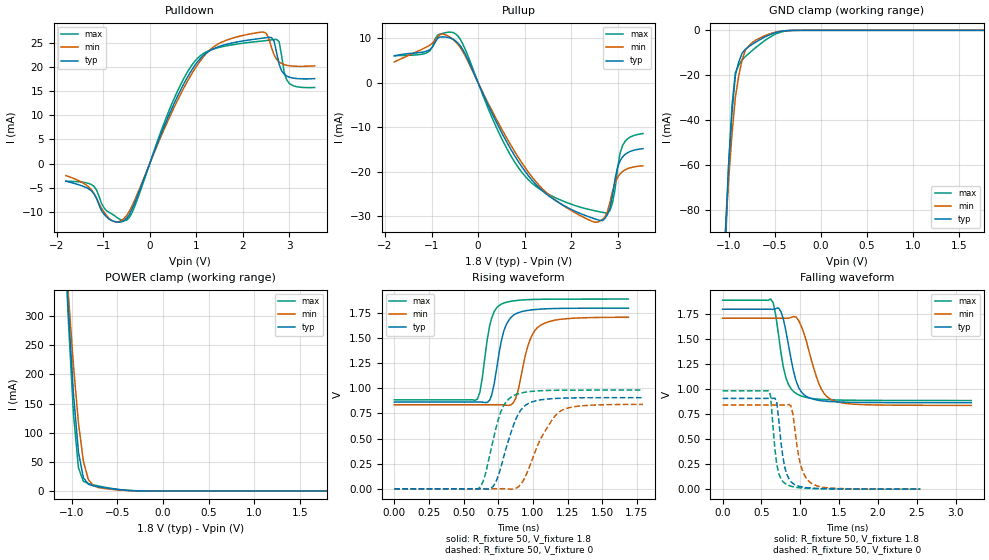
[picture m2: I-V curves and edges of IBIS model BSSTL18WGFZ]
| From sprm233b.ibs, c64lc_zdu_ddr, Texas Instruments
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|   Model Cell BSSTL18WGFZ
[Model]   BSSTL18WGFZ
Model_type   I/O
Polarity   Non-Inverting
Enable   Active-Low
Vinl =  0.8
Vinh =  1
Cref =  15.0000pF
Rref =  100.0000M
Vref =  0V
Vmeas =  0.9
C_comp   1.243651p   1.166975p   1.3173p
[Model Spec]
Vinl   0.8   0.755   0.845
Vinh   1   0.955   1.045
[Temperature Range]   25   125   -40
[Voltage Range]   1.8   1.71   1.89
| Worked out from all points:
|   slope of the pulldown table from 0 to 0.27 V, typ, clamps not added: 40.2 ohm
|   slope of the pullup table from 0 to 0.27 V, typ, clamps not added: 43.4 ohm
|   GND clamp passes 1 mA (typ) near -0.49 V on its own axis
|   POWER clamp passes 1 mA (typ) near -0.39 V on its own axis
|   rising waveform, R_fixture 50, V_fixture 1.8: 20-80 % time 80.1ps typ, 97.2ps min, 67.3ps max; typ from 0.864 V to 1.8 V
|   rising waveform, R_fixture 50, V_fixture 0: 20-80 % time 126ps typ, 172ps min, 109ps max; typ from 0 V to 0.908 V
|   falling waveform, R_fixture 50, V_fixture 1.8: 20-80 % time 155ps typ, 208ps min, 135ps max; typ from 1.8 V to 0.865 V
|   falling waveform, R_fixture 50, V_fixture 0: 20-80 % time 96.2ps typ, 117ps min, 79.5ps max; typ from 0.908 V to 0.001 V
[POWER_clamp]
|   voltage   I(typ)   I(min)   I(max)
-1.8V     2.924A     2.487A     3.338A
-1.055V   360.4mA    379.2mA    352.9mA
-1.036V   307mA      335.2mA    290.5mA
-1.018V   260.5mA    295.4mA    238.1mA
-981.8mV  167.5mA    215.8mA    133.1mA
-927.3mV  67.32mA    117.4mA    40.14mA
-872.7mV  22.56mA    51.06mA    16.61mA
-818.2mV  11.6mA     19.66mA    12.51mA
-763.6mV  8.74mA     9.202mA    10.43mA
-654.5mV  5.816mA    4.325mA    6.849mA
-272.7mV  209.5uA    104.6uA    156.2uA
1.8V      20.65nA    121nA      17.98nA
[Pulldown]
|   voltage   I(typ)   I(min)   I(max)
-1.8V     -3.616mA   -2.48mA    -3.623mA
-1.2V     -6.175mA   -6.104mA   -4.679mA
-818.2mV  -11.73mA   -11.74mA   -10.36mA
-490.9mV  -11.25mA   -10.65mA   -11.63mA
654.5mV   15.01mA    14.16mA    16.12mA
1.309V    23.41mA    23.6mA     23.46mA
2.455V    25.94mA    27.14mA    25.35mA
2.618V    26.01mA    23.98mA    25.55mA
2.727V    22.94mA    21.54mA    25.65mA
2.836V    19.15mA    20.65mA    22.22mA
3V        17.85mA    20.21mA    16.58mA
3.545V    17.54mA    20.19mA    15.71mA
[Pullup]
|   voltage   I(typ)   I(min)   I(max)
-1.8V     5.97mA     4.648mA    6.042mA
-1.091V   7.105mA    8.064mA    6.729mA
-818.2mV  10.22mA    10.77mA    10.87mA
-490.9mV  9.425mA    9.254mA    11mA
872.7mV   -17.83mA   -16.9mA    -19.16mA
1.418V    -24.61mA   -24.22mA   -24.52mA
2.182V    -29.34mA   -29.77mA   -27.93mA
2.564V    -30.79mA   -31.35mA   -28.9mA
2.836V    -28.2mA    -26.82mA   -28.68mA
3V        -19.04mA   -21.3mA    -19.15mA
3.109V    -16.66mA   -19.95mA   -14.1mA
3.545V    -14.83mA   -18.7mA    -11.44mA
[GND_clamp]
|   voltage   I(typ)   I(min)   I(max)
-1.8V     -3.609A    -2.849A    -4.282A
-1.036V   -90.86mA   -90.81mA   -98.4mA
-1V       -59.97mA   -66.44mA   -59.97mA
-963.6mV  -36.36mA   -46.14mA   -33.47mA
-927.3mV  -20.02mA   -29.92mA   -18.88mA
-890.9mV  -14.12mA   -20.26mA   -15.57mA
-854.5mV  -10.24mA   -13.24mA   -13.16mA
-818.2mV  -8.387mA   -8.861mA   -11.65mA
-709.1mV  -5.316mA   -4.454mA   -7.779mA
-490.9mV  -974.7uA   -808.7uA   -1.627mA
-345.5mV  -83.88uA   -97.13uA   -147.7uA
1.764V    -13.07nA   612.8nA    1.397nA
[Ramp]
| variable   typ   min   max
dV/dt_f  0.7607424/0.2533543n  0.7131334/0.3339664n  0.8127808/0.2287211n
dV/dt_r  0.7293766/0.1945862n   0.677097/0.252619n   0.7897642/0.1720576n
R_load = 50
[Rising Waveform]
R_fixture = 50
V_fixture = 1.8
V_fixture_min = 1.71
V_fixture_max = 1.89
|   time   V(typ)   V(min)   V(max)
0s        863.6mV    836.9mV    886mV
600ps     863.6mV    836.9mV    894.1mV
618ps     864.2mV    836.9mV    966.2mV
669ps     859.8mV    836.9mV    1.473V
702ps     929.5mV    836.8mV    1.698V
789ps     1.567V     835.2mV    1.849V
876ps     1.743V     900.4mV    1.875V
963ps     1.777V     1.421V     1.884V
1.047ns   1.789V     1.621V     1.887V
1.689ns   1.799V     1.708V     1.89V
[Rising Waveform]
R_fixture = 50
V_fixture = 0
V_fixture_min = 0
V_fixture_max = 0
|   time   V(typ)   V(min)   V(max)
0s        46.69uV    44.04uV    44.81uV
603ps     70.93uV    43.61uV    -1.627mV
657ps     -1.173mV   60.84uV    143.9mV
732ps     66.53mV    43.83uV    597.2mV
786ps     301.8mV    903.3uV    821mV
879ps     700.5mV    5.422mV    938.9mV
969ps     851mV      197.5mV    967.1mV
1.062ns   887mV      513.7mV    977.2mV
1.191ns   901.4mV    766.2mV    981.8mV
1.794ns   907.7mV    840.5mV    983.6mV
[Falling Waveform]
R_fixture = 50
V_fixture = 1.8
V_fixture_min = 1.71
V_fixture_max = 1.89
|   time   V(typ)   V(min)   V(max)
0s        1.8V       1.71V      1.89V
618ps     1.8V       1.71V      1.902V
651ps     1.799V     1.71V      1.864V
717ps     1.814V     1.71V      1.559V
813ps     1.588V     1.709V     1.118V
912ps     1.181V     1.727V     977.9mV
1.011ns   974.9mV    1.634V     932.9mV
1.239ns   888.5mV    1.056V     900.5mV
1.401ns   876.1mV    895.2mV    894mV
3.201ns   864.8mV    838.6mV    886.8mV
[Falling Waveform]
R_fixture = 50
V_fixture = 0
V_fixture_min = 0
V_fixture_max = 0
|   time   V(typ)   V(min)   V(max)
0s        908.3mV    842.3mV    983.8mV
594ps     908.3mV    842.3mV    986.6mV
618ps     908.3mV    842.3mV    930mV
696ps     875.1mV    842.3mV    253.3mV
774ps     331.5mV    842.2mV    77.6mV
828ps     144.8mV    844.1mV    46.26mV
906ps     57.63mV    747.4mV    24.97mV
1.008ns   25.21mV    231.8mV    13.05mV
1.137ns   11.89mV    63.04mV    7.077mV
2.544ns   1.208mV    1.758mV    768.9uV
